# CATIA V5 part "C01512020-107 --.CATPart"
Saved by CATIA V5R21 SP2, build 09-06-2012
Part number: C01512020-107
Revision: ---
Description: PROPRIETARY NOTICE (do not delete / modify)  ***************************************************************************************************  LA SOCIETE EN COMMANDITE  AIRBUS CANADA  ("AIRBUS CANADA")  PAR  L'INTERMEDIAIRE  DE  SES  DIVISIONS  ET/OU  FILIALES  CORPORATIVES,  FOURNIT  LES PRESENTES  INFORMATIONS  AU  GOUVERNEMENT  A  TITRE CONFIDENTIEL. CES  INFORMATIONS ONT UNE TENEUR CONFIDENTIELLE,  AVEC DROITS DE PROPRIETE,  ET NOUS LES CONSIDERONS  EXCLUS  DE   L'APPLICATION  DE  LA LOI SUR L'ACCES A L'INFORMATION  (CANADA),  LES  LOIS  SUR  L'ACCES  A  L'INFORMATION  EUROPEENNES,  LE FREEDOM OF INFORMATION ACT (ETATS-UNIS) ET D'AUTRES LOIS SEMBLABLES. ELLES  PEUVENT  AUSSI  CONSTITUER DES SECRETS INDUSTRIELS DE NOTRE SOCIETE OU DE TIERCES PARTIES. LA DIVULGATION  PUBLIQUE  DE CES  INFORMATIONS NUIRAIT A AIRBUS CANADA OU A DES TIERCES PARTIES.  CES INFORMATIONS PEUVENT EGALEMENT CONTENIR  DES DONNEES QUI SONT CONTROLEE PAR DES LOIS DE CONTROLE DES EXPORTATIONS DU CANADA, L’EUROPE OU LES  ETATS-  UNIS. TOUTE EXPORTATION OU REEXPORTATION DE DONNEES CONTROLEES SANS AUTORISATION EST STRICTEMENT INTERDITE.  TOUTE INTENTION DE LES DIVULGUER EN TOUT OU EN PARTIE DEVRA ETRE SIGNIFIEE A L'AVANCE ET PAR ECRIT AU VICE-  PRESIDENT, SERVICES JURIDIQUES ET CONFORMITE ET SECRETAIRE CORPORATIF D'AIRBUS CANADA.    AIRBUS CANADA LIMITED PARTNERSHIP  ("AIRBUS CANADA"),  BY ITS AFFILIATES AND/OR SUBSIDIARIES, PROVIDES THIS  INFORMATION TO THE GOVERNMENT IN CONFIDENCE. THIS IS PROPRIETARY CONFIDENTIAL INFORMATION WHICH WE CONSIDER  EXCLUDED  FROM  THE  APPLICATION OF THE ACCESS TO INFORMATION ACT (CANADA),  THE FREEDOM OF INFORMATION ACT  (U.S.A.),  THE ACCESS TO INFORMATION LAWS IN EUROPE, AND OTHER SIMILAR LEGISLATION. AND MAY ALSO CONSTITUTE  TRADE SECRETS OF OUR  COMPANY OR THIRD PARTIES.  PUBLIC  RELEASE  OF  THIS INFORMATION  WOULD BE HARMFUL TO  AIRBUS CANADA OR THIRD PARTIES.  THIS  INFORMATION  MAY  ALSO  CONTAIN DATA THAT IS CONTROLLED BY CANADIAN,  EUROPEAN, OR U.S.A. EXPORT CONTROL LAWS. ANY UNAUTHORIZED EXPORT OR RE-EXPORT OF ANY EXPORT CONTROLLED DATA  IS STRICTLY PROHIBITED  ANY INTENTION TO DISCLOSE SUCH INFORMATION,  OR  PART THEREOF,  MUST BE NOTIFIED IN  ADVANCE AND IN WRITING TO THE VICE PRESIDENT, LEGAL AND COMPLIANCE AND CORPORATE SECRETARY OF AIRBUS CANADA.        LES RENSEIGNEMENTS,  LES DONNEES  ET  DESSINS  TECHNIQUES  DIVULGUES  DANS  LES PRESENTES SONT LA PROPRIETE  EXCLUSIVE DE LA SOCIETE EN COMMANDITE AIRBUS CANADA ("AIRBUS CANADA") OU COMPORTENT DES DROITS DE PROPRIETE  APPARTENANT  A  AUTRUI ET NE PEUVENT ETRE DIVULGUES  A  QUICONQUE  NI  UTILISES PAR QUI QUE CE SOIT SANS LE  CONSENTEMENT  ECRIT  D’AIRBUS  CANADA.  LE DETENTEUR DES  PRESENTES  S'ENGAGE, DANS TOUTES CIRCONSTANCES, A  GARDER CONFIDENTIELS LES DONNEES ET DESSINS TECHNIQUES QU'ELLES CONTIENNENT.   CE QUI PRECEDE NE S'APPLIQUE  PAS  AUX PERSONNES  QUI  ONT DES DROITS DE PROPRIETE SUR CES RENSEIGNEMENTS,  DONNEES TECHNIQUES ET DESSINS  DANS LA MESURE OU CES DROITS EXISTENT.    THE INFORMATION,  TECHNICAL DATA  AND  DESIGNS DISCLOSED HEREIN ARE THE EXCLUSIVE PROPERTY OF AIRBUS CANADA  LIMITED PARTNERSHIP  ("AIRBUS CANADA")  OR  CONTAIN PROPRIETARY RIGHTS OF OTHERS  AND ARE NOT TO BE USED OR  DISCLOSED  TO  OTHERS WITHOUT THE WRITTEN CONSENT OF AIRBUS CANADA.  THE RECIPIENT OF THIS DOCUMENT, BY ITS  RETENTION  AND  USE  AGREES TO  HOLD  IN  CONFIDENCE  THE  TECHNICAL DATA AND DESIGNS CONTAINED HEREIN. THE  FOREGOING SHALL NOT APPLY TO PERSONS HAVING PROPRIETARY RIGHTS TO SUCH INFORMATION,  TECHNICAL DATA OR SUCH  DESIGNS TO THE EXTENT THAT SUCH RIGHTS EXIST.    Copyright 2020 Airbus Canada Limited Partnership. All Rights Reserved.  ***********************************
Property "Title": "LEVER, GIRT BAR, PASS SVCE DR"
Property "Dataset Type": "DETAIL"
Property "Supplier Name And CAGE Code": "AIRBUS CANADA LIMITED PARTNERSHIP L0J48"
Property "Major Supplier Code": "LP"
Property "3D Only": "N/A"
Property "Material Form": "BAR - FLAT"
Property "Finish Code": "S010"
Property "PCCN": "2"
Property "Organization": "DESIGN"
Property "Design Authority Program": "BD-500"
Property "Color Coded": "N/A"
Property "Thickness": 1.25
Property "Inside Diameter": 0
Property "Outside Diameter": 0
Property "Length": 0
Property "Width": 2.5
Property "Wall": 0
Property "Wire Gauge": "-"
Property "Alloy": "15-5PH"
Property "Final Condition": "H1025"
Property "Density": "N/A"
Property "Form": "N/A"
Property "Grade/Composition": "N/A"
Property "Material Class": "N/A"
Property "Mesh Cell Size": "N/A"
Property "Standard Spec Die": "N/A"
Property "Type": "N/A"
Property "Style": "N/A"
Property "MFG Process": "MACHINED"
Property "Material Specification Production": "AMS5659"
Property "Material Description Production": "CRES"
Property "Dimensions": "DIMENSIONS ARE IN INCHES"
Property "Roughness": "ALL MACHINED SURFACES 125 Ra MAX"
Property "Eng. Tolerances": "LINEAR .XX= +/-.03; .XXX= +/-.010; ANGULAR= +/-0.5 DEG"
Property "Tool Design Tolerances": "LINEAR .X= +/-.06; .XX= +/-.015; .XXX= +/-.005; .XXXX= +/-.001; ANGULAR= +/-0.5 DEG"
Property "Project": "BA"
Publications: "PartBody"
Material "CRES-PH-15-5-BAR": density 7833.41 kg/m3
Bounding box of the stored display mesh (mm): x -9.804 to 68.58, y -24.091 to 31.359, z -19.096 to 10.921
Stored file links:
  C:\Users\CQQZ006\Desktop\A220钢钛件\舱门\C01512020-107\C01512020-107 --.CATPart
  I:\Standard\Materials\Textures\steel100.jpeg

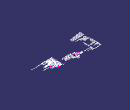
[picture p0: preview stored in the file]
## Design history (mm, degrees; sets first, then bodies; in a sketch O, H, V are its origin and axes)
AxisSystem1 "Absolute Axis System": origin (0, 0, 0), X (1, 0, 0), Y (0, 1, 0), Z (0, 0, 1)
Part_3D_Annotations1 "CATTPSSet"
Set1 "References"
  DatumSurface1
Set2 "Geometrical Set for 3D Annotations"
  Set3 "No Show Geometry"
    Extract1 "Extract.1_DATUM_A"
    Extract2 "Extract.1_DATUM_B": ExtractElem face
    Extract3 "Extract.1_DATUM_C": ExtractElem face of Assemble4
    Plane1
    MultiExtract1: ListOfMultiExtractConstraints (MultiExtractConstraint face of Pocket2 from Sketch5.L2; MultiExtractConstraint face of Fillet4; MultiExtractConstraint face of Fillet4; MultiExtractConstraint face of Pocket2 from Sketch5.L1; MultiExtractConstraint face of Fillet5; MultiExtractConstraint face of Fillet4; MultiExtractConstraint face of Fillet4; MultiExtractConstraint face of Fillet4; MultiExtractConstraint face of Pocket2 from Sketch5.L3; MultiExtractConstraint face of Fillet4; MultiExtractConstraint face of Fillet6; MultiExtractConstraint face of Pocket5 from Sketch9.L3; MultiExtractConstraint face of Fillet6; MultiExtractConstraint face of Pocket4 from Sketch8.L2; MultiExtractConstraint face of Fillet5)
    MultiExtract2: ListOfMultiExtractConstraints (MultiExtractConstraint face of Hole3; MultiExtractConstraint face of Hole3)
    MultiExtract3: ListOfMultiExtractConstraints (MultiExtractConstraint face of Hole2; MultiExtractConstraint face of Hole2)
Set4 "Construction_Geometry"
  Plane2: type Offset, RefPlane yz-plane, Offset 9.5504
  Plane3: type Offset, RefPlane Plane2, Offset 4.0894
  Plane4: type Offset, RefPlane Plane5, Offset 11.43
  Plane5: type Offset, RefPlane Plane3, Offset 43.5102
  Plane6: type Offset, RefPlane yz-plane, Offset 9.8044, reversed
  Plane7: type Offset, RefPlane Plane6, Offset 3.81
  Plane8: type Offset, RefPlane Plane2, Offset 3.81, reversed
  Plane9: type Offset, RefPlane Plane2, Offset 11.43, reversed
  Plane10: type Offset, RefPlane Plane6, Offset 2.6162
  Plane11: type Offset, RefPlane Plane2, Offset 2.6162, reversed
Body1 "PartBody" (main body)
  Sketch1 on yz-plane, origin (0, 0, 0), H (0, 1, 0), V (0, 0, 1)
    construction line L1 (0, 0) -> (21.844, 0)
    circle A1 centre (21.844, 0) radius 4.7625
    arc A2 centre (-20.2853, -15.2861) radius 3.81 from (-23.3385, -13.007) to (-18.7873, -18.7892) ccw
    arc A3 centre (21.844, 0) radius 9.525 from (22.4532, -9.5055) to (22.4532, 9.5055) ccw
    line L2 (-8.7525, 6.5333) -> (-23.3385, -13.007)
    point P2 (-20.2853, -15.2861)
    line L3 (22.4532, 9.5055) -> (0.6985, 10.8996)
    construction circle A4 centre (0, 0) radius 2.5019
    construction line L4 (-20.2853, -15.2861) -> (0, 0)
    arc A5 centre (0, 0) radius 10.922 from (0.6985, 10.8996) to (-8.7525, 6.5333) ccw
    construction arc A6 centre (0, 0) radius 10.922 from (2.8446, -10.5451) to (0.6985, -10.8996) ccw
    line L5 (-1.643, -11.4579) -> (-18.7873, -18.7892)
    point P7 (25.1512, 0)
    line L6 (22.4532, -9.5055) -> (0.6985, -10.8996)
    point P9 (0.6985, -10.8996)
    arc A7 centre (1.1533, -17.9971) radius 7.112 from (0.6985, -10.8996) to (-1.643, -11.4579) ccw
    length L1 = 21.844
    radius A3 = 9.525
    radius A1 = 4.7625
    radius A2 = 3.81
    radius A4 = 2.5019
    angle L4 L1 = 143
    length L4 = 25.4
    radius A5 = 10.922
    radius A7 = 7.112
    horizontal: L1 H
    concentricity: P2 A2
    tangency: L2 A2, L3 A3, L2 A5, L3 A5, A6 L3, L6 A3, L6 A6, L5 A2, A7 L6, A7 L5, A7 A6
    coincidence: P7 H, L5 P7, L6 P9
  Pad1: profile Sketch1, direction (1, 0, 0), up to Plane4, opposite side up to Plane6
  Body2
    Sketch2 on xy-plane, origin (0, 0, 0), H (1, 0, 0), V (0, 1, 0)
      reference intersected line E1 through (9.5504, 0) direction (0, 1) from Plane2
      intersected line E2 through (13.6398, 0) direction (0, 1) from Plane3
      reference intersected line E3 through (68.58, 0) direction (0, 1) from Plane4
      projected line E4 through (0, 0) direction (1, 0)
      line L1 (57.15, 5.5448) -> (13.6398, 5.5448)
      line L2 (68.58, 3.175) -> (57.15, 3.175)
      intersected line E5 through (57.15, 0) direction (0, 1) from Plane5
      point P11 (9.5504, 5.5448)
      line L3 (9.5504, 10.16) -> (9.5504, 38.1)
      line L4 (9.5504, 38.1) -> (68.58, 38.1)
      point P13 (68.58, 38.1)
      line L5 (68.58, 38.1) -> (68.58, 3.175)
      line L6 (9.5504, 10.16) -> (13.6398, 10.16)
      line L7 (13.6398, 10.16) -> (13.6398, 5.5448)
      line L8 (57.15, 5.5448) -> (57.15, 3.175)
      point P14 (-43.18, 5.5563)
      point P20 (57.15, 2.794)
      distance L1 E4 = 5.5448
      distance L2 E4 = 3.175
      distance L4 E4 = 38.1
      distance L6 E4 = 10.16
      distance L2 P20 = 0.381
      horizontal: L1 H, L2 H, L4 H, L6 H
      coincidence: P11 L1, P11 E1, P13 E3, L8 E5, P11 L3, L7 E2
      vertical: L3 V, L5 V, L7 V
    Groove1: profile Sketch2, axis edge [XY plane of AxisSystem1 | ZX plane of AxisSystem1], angle 360
  Assemble1: tool Body2
  Fillet1: radius 0.254, on edge [face of Groove1 from Sketch2.L1 | face of Groove1 from Sketch2.L7]
  Fillet2: radius 3.556, on edge [face of Groove1 from Sketch2.L6 | face of Groove1 from Sketch2.L3]
  Chamfer1: length 0.254, angle 45, on 1 edge
  Sketch3 on Plane2, origin (9.5504, -2.0764, -1.2021), H (0, 1, 0), V (0, 0, 1)
    point P1 (23.9204, 1.2021)
    construction line L1 (2.0764, 1.2021) -> (23.9204, 1.2021)
    point P2 (23.9204, 1.2021)
    length L1 = 21.844
    horizontal: L1 H
    coincidence: P2 P1
  Hole1: placed by Sketch3, at (9.5504, 21.844, 0) direction (-1, 0, 0), diameter 12.6987, depth 5.08
  Body3
    Sketch4 on Plane9, origin (-1.8796, 0, 0), H (0, 1, 0), V (0, 0, 1)
      arc A1 centre (0, 0) radius 10.922 from (-8.7525, 6.5333) to (0.6985, -10.8996) ccw
      projected line E1 (-18.7873, -18.7892) -> (-1.643, -11.4579) from edge [start face of Pad1 | face of Pad1 from Sketch1.L5]
      projected line E2 (-18.7873, -18.7892) -> (-1.643, -11.4579) from edge [start face of Pad1 | face of Pad1 from Sketch1.L5]
      projected arc E3 centre (-20.2853, -15.2861) radius 3.81 from (-18.7873, -18.7892) to (-23.3385, -13.007) cw from edge [face of Pad1 from Sketch1.A2 | start face of Pad1]
      point P3 (-18.7873, -18.7892)
      projected line E4 (-23.3385, -13.007) -> (-8.7525, 6.5333) from edge [face of Pad1 from Sketch1.L2 | start face of Pad1]
      projected line E5 (-8.7525, 6.5333) -> (-8.7525, 6.5333) from edge [face of Pad1 from Sketch1.L2 | start face of Pad1]
      point P6 (-8.7525, 6.5333)
      projected arc E6 centre (1.1533, -17.9971) radius 7.112 from (-1.643, -11.4579) to (0.6985, -10.8996) cw from edge [start face of Pad1 | face of Pad1 from Sketch1.A7]
      projected arc E7 centre (1.1533, -17.9971) radius 7.112 from (0.6985, -10.8996) to (-1.643, -11.4579) ccw from edge [start face of Pad1 | face of Pad1 from Sketch1.A7]
      projected line E8 (0.6985, -10.8996) -> (22.4532, -9.5055) from edge [start face of Pad1 | face of Pad1 from Sketch1.L6]
      radius A1 = 10.922
      coincidence: P3 P6
    Pocket1: profile Sketch4, direction (-1, 0, 0), up to Plane6
    Fillet3: radius 1.524, on edge [start face of Pocket1 | face of Pocket1 from Sketch4.A1]
  Assemble2: tool Body3
  Body4
    Sketch5 on Plane7, origin (-5.9944, 0, 0), H (0, 1, 0), V (0, 0, 1)
      line L1 (6.9342, -3.2335) -> (6.9342, 3.2335)
      line L2 (-4.3476, -12.7) -> (6.9342, -3.2335)
      line L3 (-4.3476, 12.7) -> (6.9342, 3.2335)
      construction circle A1 centre (0, 0) radius 6.9342
      point P3 (0, 0)
      line L4 (-4.3476, 12.7) -> (38.1, 12.7)
      line L5 (38.1, 12.7) -> (38.1, -12.7)
      line L6 (38.1, -12.7) -> (-4.3476, -12.7)
      construction circle A2 centre (0, 0) radius 4.7625
      angle L3 L1 = 50
      angle L1 L2 = 50
      distance V L5 = 38.1
      distance H L4 = 12.7
      distance L3 A2 = 2.1717 (reference)
      distance L1 A2 = 2.1717 (reference)
      radius A2 = 4.7625
      radius A1 = 6.9342
      coincidence: P3 O
      tangency: L2 A1, L3 A1, L1 A1
      perpendicularity: L5 L4, L5 L6, L1 L6
      symmetry: L4 L6 H
    Pocket2: profile Sketch5, direction (-1, 0, 0), up to Plane10, opposite side up to Plane11
    Fillet4: radius 1.524, on edge [end face of Pocket2 | face of Pocket2 from Sketch5.L1]; edge [face of Pocket2 from Sketch5.L1 | start face of Pocket2]; edge [face of Pocket2 from Sketch5.L2 | start face of Pocket2]; edge [face of Pocket2 from Sketch5.L3 | start face of Pocket2]; edge [end face of Pocket2 | face of Pocket2 from Sketch5.L3]; edge [face of Pocket2 from Sketch5.L2 | end face of Pocket2]
  Assemble3: tool Body4
  Body5
    Sketch6 on xy-plane, origin (0, 0, 0), H (1, 0, 0), V (0, 1, 0)
      circle A1 centre (63.9572, 0) radius 1.0287
      point P1 (63.9572, 0)
      reference intersected line E1 through (68.58, 0) direction (0, 1) from end face of Pad1
      reference projected line E2 through (0, 0) direction (1, 0) from axis of face of Groove1 from Sketch2.L2
      radius A1 = 1.0287
      distance P1 E1 = 4.6228
      coincidence: P1 E2
    Pocket3: profile Sketch6, direction (0, 0, -1), up to face of Groove1 from Sketch2.L2, opposite side up to face of Groove1 from Sketch2.L2
  Assemble4: tool Body5
  Hole2
  Sketch7 on face, origin (-9.8044, -5.5385, 7.4506), H (0, 1, 0), V (0, 0, -1)
    point P1 (5.5385, 7.4506)
    reference projected arc E1 centre (5.5385, 7.4506) radius 10.922 from (-3.214, 0.9173) to (6.237, -3.449) ccw from edge [start face of Pad1 | face of Pad1]
    concentricity: E1 P1
  Hole3: placed by Sketch7, at (-9.8044, 0, 0) direction (1, 0, 0), diameter 5.6134, depth 63.5, V-bottom angle 120
  Chamfer2: length 1.016, angle 45, on edge [face of Groove1 from Sketch2.L2 | end face of Pad1]
  Body6
    Sketch8 on Plane9, origin (-1.8796, 0, 0), H (0, 1, 0), V (0, 0, 1)
      projected line E3 (-3.0602, -12.0639) -> (-18.7873, -18.7892) from edge [face of Pad1 from Sketch1.L5 | start face of Pocket1]
      point P5 (-3.0602, -12.0639)
      point P6 (-18.7873, -18.7892)
      construction circle A1 centre (0, 0) radius 7.0612
      construction line L1 through (0, -7.0612) direction (1, 0)
      point P7 (0, -7.0612)
      line L2 (12.7, -7.0612) -> (-12.7, -7.0612)
      point P10 (3.3756, -7.0612)
      line L3 (-12.7, -19.7612) -> (12.7, -19.7612)
      line L4 (12.7, -19.7612) -> (12.7, -7.0612)
      line L5 (-12.7, -7.0612) -> (-12.7, -19.7612)
      radius A1 = 7.0612
      distance L4 V = 12.7
      length L4 = 12.7
      distance L5 L4 = 25.4
      coincidence: E3 P6, E3 P5, L1 P7, P7 A1, P10 L1, P10 L2
      horizontal: L1 H, L2 H, L3 H
      tangency: L1 A1
      vertical: L4 V, L5 V
    Pocket4: profile Sketch8, direction (-1, 0, 0), up to Plane8, opposite side up to Plane10
    Fillet5: radius 1.524, on edge [start face of Pocket4 | face of Pocket4 from Sketch8.L2]; edge [face of Pocket4 from Sketch8.L2 | end face of Pocket4]
  Assemble5: tool Body6
  Body7
    Sketch9 on Plane10, origin (-7.1882, 0, 0), H (0, 1, 0), V (0, 0, 1)
      line L1 (12.6792, 13.6955) -> (-12.1896, 13.6955)
      line L2 (-12.1896, 13.6955) -> (-12.1896, 7.0612)
      line L3 (-12.1896, 7.0612) -> (12.6792, 7.0612)
      line L4 (12.6792, 7.0612) -> (12.6792, 13.6955)
      construction circle A1 centre (0, 0) radius 7.0612
      radius A1 = 7.0612
      horizontal: L1 H, L3 H
      vertical: L2 V, L4 V
      tangency: L3 A1
    Pocket5: profile Sketch9, direction (1, 0, 0), up to Plane11
    Fillet6: radius 1.524, on edge [start face of Pocket5 | face of Pocket5 from Sketch9.L3]; edge [end face of Pocket5 | face of Pocket5 from Sketch9.L3]
  Assemble6: tool Body7
  Body8
    Sketch10 on Plane9, origin (-1.8796, 0, 0), H (0, 1, 0), V (0, 0, 1)
      reference projected arc E1 centre (-20.2853, -15.2861) radius 3.81 from (-18.7873, -18.7892) to (-23.3385, -13.007) cw from edge [face of Pad1 from Sketch1.A2 | start face of Pocket1]
      projected arc E2 centre (0, 0) radius 10.922 from (0.6985, -10.8996) to (0.6985, 10.8996) cw from edge [face of Pad1 | start face of Pad1]
      projected arc E3 centre (0, 0) radius 10.922 from (-8.927, -6.2927) to (0.6985, -10.8996) ccw from edge [face of Pad1 | start face of Pad1]
      point P3 (0.6985, -10.8996)
      point P4 (0.6985, 10.8996)
      reference projected line E4 (-23.3385, -13.007) -> (-12.3222, 1.7511) from edge [face of Pad1 from Sketch1.L2 | start face of Pocket1]
      line L1 (-15.0943, -6.2088) -> (-15.7829, -7.1312)
      arc A1 centre (-20.2853, -15.2861) radius 3.81 from (-18.7873, -18.7892) to (-16.7266, -13.9254) ccw
      arc A2 centre (-10.0836, -11.3855) radius 7.112 from (-16.7266, -13.9254) to (-15.7829, -7.1312) cw
      projected line E5 (-3.0602, -12.0639) -> (-18.7873, -18.7892) from edge [face of Pad1 from Sketch1.L5 | start face of Pocket1]
      projected line E6 (-1.643, -11.4579) -> (-18.7873, -18.7892) from edge [face of Pad1 from Sketch1.L5 | start face of Pocket1]
      point P11 (-3.0602, -12.0639)
      point P12 (-18.7873, -18.7892)
      arc A3 centre (-12.0411, -8.4878) radius 3.81 from (-8.927, -6.2927) to (-15.0943, -6.2088) ccw
      arc A4 centre (1.1533, -17.9971) radius 7.112 from (0.6985, -10.8996) to (-1.643, -11.4579) ccw
      construction circle A5 centre (0, 0) radius 5.207
      construction circle A6 centre (0, 0) radius 7.239
      distance L1 E4 = 2.54
      radius A2 = 7.112
      radius A3 = 3.81
      radius A4 = 7.112
      radius A5 = 5.207
      radius A6 = 7.239
      coincidence: A1 E1, E2 P3, E5 P12, E2 P4, E5 P11
      tangency: A2 A1, A2 L1, A3 L1, A3 E2, A4 E2, A4 E5
    Pocket6: profile Sketch10, direction (1, 0, 0), up to Plane8, opposite side length 2.54
    Fillet7: radius 1.524, on edge [end face of Pocket6 | face of Pocket6 from Sketch10.A3]
  Assemble7: tool Body8
Set5 "CHANGE INFORMATION 3"
  Offset1: Offset MultiExtract2, Length 0.0254
  Offset2: Offset MultiExtract3, Length 0.0254
Set6 "VIEW_A_GS"
  Split1 "Imperfect threads"
Set7 "CHANGE INFORMATION 5"
  Offset3: Offset MultiExtract1, Length 0.0127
